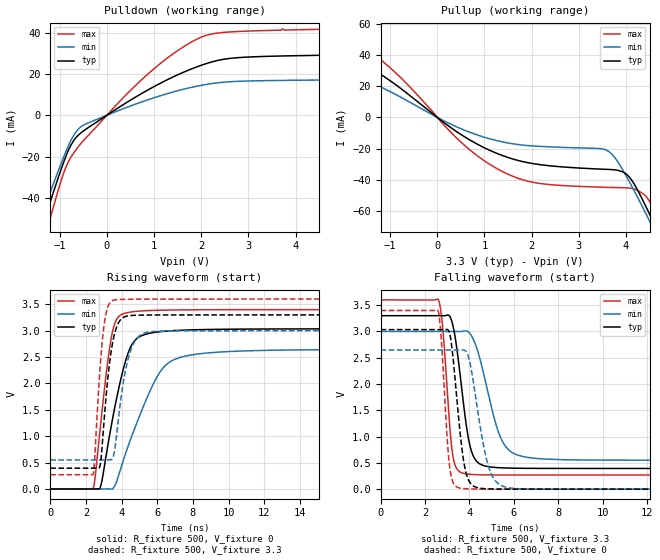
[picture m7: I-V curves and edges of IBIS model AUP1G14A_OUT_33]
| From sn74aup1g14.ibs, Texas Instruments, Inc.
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[Model]   AUP1G14A_OUT_33
Model_type  Output
Vref =   0
Rref =   1E6
Cref =   30p
Vmeas =   1.65
| variable   typ   min   max
C_comp   2.81pF   1.90pF   4.21pF
| C_pullup   3.21pF   1.90pF   4.21pF
| C_pulldown   2.42pF   2.21pF   2.99pF
[Temperature Range]   40   100   -40
| Ambient temperature   25   85   -40
[Voltage range]   3.3   3   3.6
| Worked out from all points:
|   slope of the pulldown table from 0 to 0.495 V, typ, clamps not added: 68.4 ohm
|   slope of the pullup table from 0 to 0.495 V, typ, clamps not added: 45.8 ohm
|   rising waveform, R_fixture 500, V_fixture 0: 20-80 % time 1.1ns typ, 1.89ns min, 693ps max; typ from 0 V to 3.04 V
|   falling waveform, R_fixture 500, V_fixture 3.3: 20-80 % time 532ps typ, 894ps min, 343ps max; typ from 3.3 V to 0.394 V
|   rising waveform, R_fixture 500, V_fixture 3.3: 20-80 % time 522ps typ, 676ps min, 407ps max; typ from 0.394 V to 3.3 V
|   falling waveform, R_fixture 500, V_fixture 0: 20-80 % time 434ps typ, 648ps min, 296ps max; typ from 3.04 V to 0 V
[Pulldown]
| AUP1G14A_OUT_33
|   Voltage   I(typ)   I(min)   I(max)
-3.6V     -218.7mA   -196.3mA   -248.6mA
-1.515V   -64.37mA   -57.31mA   -75.82mA
-1.39V    -55.35mA   -49.29mA   -65.41mA
-1.275V   -47.14mA   -42mA      -55.89mA
-870mV    -19.93mA   -17.62mA   -25.18mA
-720mV    -12.85mA   -10.38mA   -18.82mA
-545mV    -8.444mA   -5.509mA   -13.51mA
940mV     13.13mA    8.018mA    21.36mA
1.5V      19.56mA    11.86mA    31.27mA
2.045V    24.53mA    14.67mA    38.2mA
3.1V      28.27mA    16.63mA    40.81mA
7.2V      29.73mA    17.36mA    42.67mA
[Pullup]
| AUP1G14A_OUT_33
|   Voltage   I(typ)   I(min)   I(max)
-3.6V     42.88mA    27.27mA    57.92mA
-2.465V   31.53mA    19.52mA    45.85mA
-1.53V    32.87mA    22.09mA    44.95mA
-755mV    18.1mA     12.64mA    24.89mA
555mV     -11.98mA   -7.942mA   -17.3mA
1.65V     -27.07mA   -17.13mA   -38.31mA
3.61V     -33.32mA   -21.39mA   -44.82mA
4.08V     -38.63mA   -41.77mA   -45.28mA
4.375V    -54.25mA   -58.9mA    -49.24mA
4.565V    -66.24mA   -70.37mA   -57.33mA
4.775V    -80.02mA   -83.29mA   -71.37mA
7.2V      -250.7mA   -240.9mA   -257mA
[Ramp]
| AUP1G14A_OUT_33
| variable   typ   min   max
dV/dt_r   1.82/1.10E-09   1.59/1.89E-09   2.04/6.95E-10
dV/dt_f   1.75/5.38E-10   1.48/9.00E-10   2.01/3.46E-10
R_load = 500
[Rising Waveform]
| AUP1G14A_OUT_33
R_fixture =   500
C_fixture =   0
L_fixture =   0
V_fixture =   0
V_fixture_min = 0
V_fixture_max = 0
|   Time   V(typ)   V(min)   V(max)
0s        24.73nV    82.54nV    2.123nV
2.41ns    -1.838uV   -5.975uV   10.23mV
2.84ns    66.48mV    -28.42uV   1.273V
3.41ns    1.174V     -2.96mV    2.84V
3.69ns    1.666V     111.4mV    3.194V
4.155ns   2.345V     600.5mV    3.327V
4.785ns   2.829V     1.191V     3.366V
6.045ns   2.977V     2.158V     3.388V
7.545ns   3.012V     2.517V     3.395V
30.7ns    3.035V     2.647V     3.399V
[Falling Waveform]
| AUP1G14A_OUT_33
R_fixture =   500
C_fixture =   0
L_fixture =   0
V_fixture =   3.3
V_fixture_min = 3
V_fixture_max = 3.6
|   Time   V(typ)   V(min)   V(max)
0s        3.3V       3V         3.6V
2.605ns   3.3V       3V         3.6V
2.795ns   3.299V     3V         3.071V
3.235ns   3.143V     3V         683.3mV
3.735ns   1.614V     3.008V     299.9mV
4.01ns    847.1mV    2.966V     282.9mV
4.325ns   528.2mV    2.687V     275.4mV
5.39ns    406.8mV    991.7mV    270mV
6.41ns    397mV      620.5mV    269.4mV
30.7ns    394.1mV    550mV      269.3mV
[Rising Waveform]
| AUP1G14A_OUT_33
R_fixture =   500
C_fixture =   0
L_fixture =   0
V_fixture =   3.3
V_fixture_min = 3
V_fixture_max = 3.6
|   Time   V(typ)   V(min)   V(max)
0s        394.1mV    550mV      269.3mV
2.4ns     394.1mV    550mV      279.2mV
2.485ns   394.2mV    550mV      545.2mV
2.785ns   432.2mV    550mV      2.253V
2.975ns   1.103V     550.2mV    2.989V
3.26ns    2.198V     551.2mV    3.48V
3.545ns   2.854V     625.8mV    3.579V
4.37ns    3.282V     2.471V     3.596V
5.385ns   3.296V     2.966V     3.599V
30.7ns    3.3V       3V         3.6V
[Falling Waveform]
| AUP1G14A_OUT_33
R_fixture =   500
C_fixture =   0
L_fixture =   0
V_fixture =   0
V_fixture_min = 0
V_fixture_max = 0
|   Time   V(typ)   V(min)   V(max)
0s        3.035V     2.647V     3.399V
2.59ns    3.035V     2.647V     3.388V
2.725ns   3.035V     2.647V     2.88V
3.1ns     2.975V     2.647V     449mV
3.54ns    1.23V      2.647V     22.51mV
3.77ns    454mV      2.644V     9.155mV
4.03ns    120.3mV    2.385V     3.913mV
4.835ns   5.883mV    462.3mV    359.7uV
5.67ns    732.2uV    33.61mV    51.4uV
30.7ns    -41.62nV   32.74nV    -29.92nV
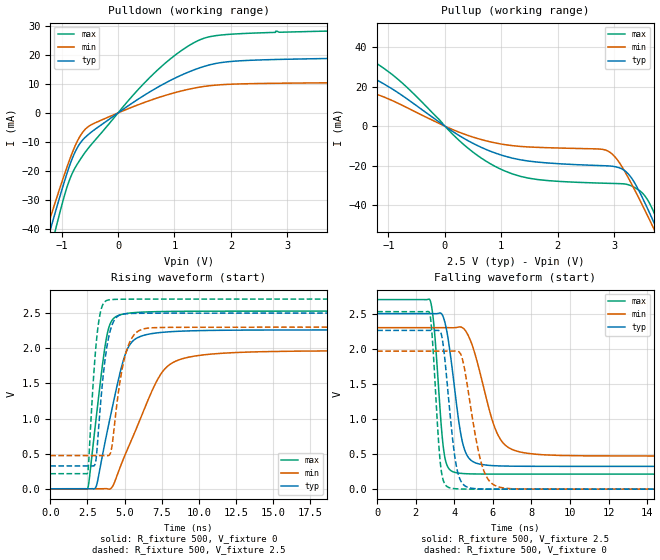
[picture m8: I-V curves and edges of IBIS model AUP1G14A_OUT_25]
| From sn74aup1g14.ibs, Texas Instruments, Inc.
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[Model]   AUP1G14A_OUT_25
Model_type  Output
Vref =   0
Rref =   1E6
Cref =   30p
Vmeas =   1.25
| variable   typ   min   max
C_comp   2.86pF   1.96pF   4.23pF
| C_pullup   3.21pF   1.96pF   4.23pF
| C_pulldown   2.51pF   2.22pF   3.08pF
[Temperature Range]   40   100   -40
| Ambient temperature   25   85   -40
[Voltage range]   2.5   2.3   2.7
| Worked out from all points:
|   slope of the pulldown table from 0 to 0.375 V, typ, clamps not added: 75.2 ohm
|   slope of the pullup table from 0 to 0.375 V, typ, clamps not added: 55.1 ohm
|   rising waveform, R_fixture 500, V_fixture 0: 20-80 % time 1.4ns typ, 2.4ns min, 861ps max; typ from 0 V to 2.26 V
|   falling waveform, R_fixture 500, V_fixture 2.5: 20-80 % time 634ps typ, 1.09ns min, 400ps max; typ from 2.5 V to 0.325 V
|   rising waveform, R_fixture 500, V_fixture 2.5: 20-80 % time 630ps typ, 806ps min, 486ps max; typ from 0.325 V to 2.5 V
|   falling waveform, R_fixture 500, V_fixture 0: 20-80 % time 507ps typ, 760ps min, 339ps max; typ from 2.26 V to 0 V
[Pulldown]
| AUP1G14A_OUT_25
|   Voltage   I(typ)   I(min)   I(max)
-3.6V     -214mA     -193.5mA   -239.7mA
-1.26V    -44.55mA   -39.92mA   -52.42mA
-1.205V   -40.74mA   -36.52mA   -48.02mA
-1.115V   -34.57mA   -31.02mA   -40.91mA
-800mV    -15.22mA   -13.22mA   -20.4mA
-685mV    -10.84mA   -8.445mA   -16.54mA
-540mV    -7.689mA   -4.911mA   -12.5mA
675mV     8.558mA    5.038mA    14.35mA
1.105V    12.9mA     7.5mA      21.28mA
1.52V     16.03mA    9.129mA    25.76mA
2.585V    18.34mA    10.19mA    27.69mA
7.2V      19.61mA    10.73mA    29.61mA
[Pullup]
| AUP1G14A_OUT_25
|   Voltage   I(typ)   I(min)   I(max)
-3.6V     37.28mA    23.5mA     50.35mA
-2.355V   24.65mA    15.21mA    35.57mA
-1.425V   26.01mA    17.2mA     35.58mA
-760mV    15.58mA    10.63mA    21.96mA
405mV     -7.279mA   -4.651mA   -11.04mA
1.05V     -15.07mA   -9.293mA   -22.54mA
2.845V    -20.04mA   -12.07mA   -28.88mA
3.17V     -22.17mA   -22.09mA   -29.2mA
3.455V    -33.67mA   -37.48mA   -32.73mA
3.685V    -47.61mA   -50.92mA   -42.5mA
3.82V     -56.28mA   -59.04mA   -51.47mA
7.2V      -294.7mA   -278.7mA   -311.5mA
[Ramp]
| AUP1G14A_OUT_25
| variable   typ   min   max
dV/dt_r   1.36/1.40E-09   1.18/2.41E-09   1.52/8.62E-10
dV/dt_f   1.31/6.40E-10   1.10/1.10E-09   1.50/4.05E-10
R_load = 500
[Rising Waveform]
| AUP1G14A_OUT_25
R_fixture =   500
C_fixture =   0
L_fixture =   0
V_fixture =   0
V_fixture_min = 0
V_fixture_max = 0
|   Time   V(typ)   V(min)   V(max)
0s        19.04nV    76.96nV    1.464nV
2.52ns    -19.26uV   -183.7nV   4.866mV
3.1ns     39.45mV    -26.1uV    1.03V
3.77ns    751.8mV    1.393mV    2.135V
4.62ns    1.584V     261.2mV    2.47V
5.135ns   1.961V     533.1mV    2.495V
5.69ns    2.126V     806.6mV    2.508V
7.415ns   2.224V     1.625V     2.522V
8.915ns   2.244V     1.853V     2.526V
32.79ns   2.261V     1.966V     2.528V
[Falling Waveform]
| AUP1G14A_OUT_25
R_fixture =   500
C_fixture =   0
L_fixture =   0
V_fixture =   2.5
V_fixture_min = 2.3
V_fixture_max = 2.7
|   Time   V(typ)   V(min)   V(max)
0s        2.5V       2.3V       2.7V
2.74ns    2.5V       2.3V       2.693V
2.955ns   2.499V     2.3V       2.3V
3.46ns    2.426V     2.3V       535.6mV
4.025ns   1.412V     2.3V       239.4mV
4.39ns    710.1mV    2.304V     224mV
4.77ns    437mV      2.161V     218.4mV
6.19ns    332.6mV    814.1mV    214.6mV
7.385ns   326.4mV    531.3mV    214.4mV
32.79ns   324.7mV    472mV      214.4mV
[Rising Waveform]
| AUP1G14A_OUT_25
R_fixture =   500
C_fixture =   0
L_fixture =   0
V_fixture =   2.5
V_fixture_min = 2.3
V_fixture_max = 2.7
|   Time   V(typ)   V(min)   V(max)
0s        324.7mV    472mV      214.4mV
2.515ns   324.7mV    472mV      226.8mV
2.98ns    335.3mV    472mV      1.789V
3.155ns   586.1mV    472mV      2.205V
3.44ns    1.348V     472.2mV    2.566V
3.805ns   2.014V     472.1mV    2.68V
4.125ns   2.312V     573.9mV    2.693V
5.08ns    2.491V     1.928V     2.698V
6.215ns   2.498V     2.272V     2.699V
32.79ns   2.5V       2.3V       2.7V
[Falling Waveform]
| AUP1G14A_OUT_25
R_fixture =   500
C_fixture =   0
L_fixture =   0
V_fixture =   0
V_fixture_min = 0
V_fixture_max = 0
|   Time   V(typ)   V(min)   V(max)
0s        2.261V     1.966V     2.528V
2.71ns    2.261V     1.966V     2.514V
2.86ns    2.26V      1.966V     2.15V
3.295ns   2.231V     1.966V     325mV
3.785ns   1.054V     1.966V     17.17mV
4.075ns   377mV      1.968V     6.117mV
4.385ns   94.51mV    1.886V     2.296mV
5.42ns    3.052mV    352.9mV    129.4uV
6.37ns    366.4uV    25.92mV    18.05uV
32.79ns   -40.91nV   13.26nV    -41.92nV
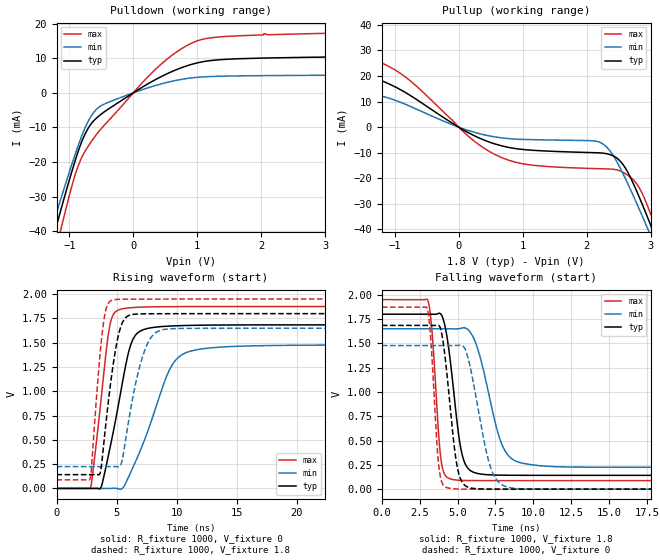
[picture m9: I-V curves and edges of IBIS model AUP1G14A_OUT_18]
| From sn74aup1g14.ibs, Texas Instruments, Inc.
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[Model]   AUP1G14A_OUT_18
Model_type  Output
Vref =   0
Rref =   1E6
Cref =   30p
Vmeas =   0.9
| variable   typ   min   max
C_comp   2.88pF   2.03pF   4.17pF
| C_pullup   3.17pF   2.03pF   4.17pF
| C_pulldown   2.60pF   2.23pF   3.12pF
[Temperature Range]   40   100   -40
| Ambient temperature   25   85   -40
[Voltage range]   1.8   1.65   1.95
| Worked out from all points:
|   slope of the pulldown table from 0 to 0.27 V, typ, clamps not added: 88.6 ohm
|   slope of the pullup table from 0 to 0.27 V, typ, clamps not added: 73.6 ohm
|   rising waveform, R_fixture 1000, V_fixture 0: 20-80 % time 1.58ns typ, 2.62ns min, 994ps max; typ from 0 V to 1.68 V
|   falling waveform, R_fixture 1000, V_fixture 1.8: 20-80 % time 758ps typ, 1.33ns min, 466ps max; typ from 1.8 V to 0.142 V
|   rising waveform, R_fixture 1000, V_fixture 1.8: 20-80 % time 1.03ns typ, 1.42ns min, 733ps max; typ from 0.142 V to 1.8 V
|   falling waveform, R_fixture 1000, V_fixture 0: 20-80 % time 682ps typ, 1.11ns min, 431ps max; typ from 1.68 V to 0 V
[Pulldown]
| AUP1G14A_OUT_18
|   Voltage   I(typ)   I(min)   I(max)
-3.6V     -208.6mA   -189.9mA   -231.7mA
-1.27V    -43.16mA   -39.01mA   -50.14mA
-1.215V   -39.42mA   -35.66mA   -45.88mA
-1.125V   -33.38mA   -30.25mA   -38.97mA
-850mV    -16.31mA   -14.68mA   -20.63mA
-710mV    -10.41mA   -8.408mA   -15.6mA
-555mV    -6.973mA   -4.411mA   -11.55mA
360mV     3.96mA     2.185mA    7.039mA
705mV     6.927mA    3.722mA    12.18mA
1.03V     8.784mA    4.527mA    15.22mA
2.04V     10.05mA    4.966mA    17.1mA
7.2V      11.18mA    5.355mA    18.77mA
[Pullup]
| AUP1G14A_OUT_18
|   Voltage   I(typ)   I(min)   I(max)
-3.6V     32.09mA    19.71mA    43.84mA
-3.16V    27.19mA    16.62mA    37.96mA
-2.12V    17.93mA    10.78mA    26.5mA
-1.525V   19.29mA    11.78mA    27.75mA
-1.155V   17.65mA    11.82mA    24.55mA
680mV     -7.373mA   -4.228mA   -12mA
2.185V    -10.05mA   -5.721mA   -16.26mA
2.485V    -12.35mA   -14.1mA    -16.81mA
2.725V    -21.81mA   -26.61mA   -20.47mA
2.94V     -34.55mA   -38.91mA   -30.08mA
3.085V    -43.74mA   -47.5mA    -39.77mA
7.2V      -334.8mA   -315.6mA   -357.6mA
[Ramp]
| AUP1G14A_OUT_18
| variable   typ   min   max
dV/dt_r   1.01/1.59E-09   0.89/2.63E-09   1.13/9.96E-10
dV/dt_f   1.00/7.63E-10   0.86/1.34E-09   1.12/4.70E-10
R_load = 1000
[Rising Waveform]
| AUP1G14A_OUT_18
R_fixture =   1000
C_fixture =   0
L_fixture =   0
V_fixture =   0
V_fixture_min = 0
V_fixture_max = 0
|   Time   V(typ)   V(min)   V(max)
0s        17.12nV    87.22nV    1.127nV
2.84ns    -18.28uV   -646.2nV   11.47mV
3.695ns   9.341mV    -15.97uV   897.8mV
4.35ns    356.4mV    100.2uV    1.615V
5.15ns    856.8mV    -3.738mV   1.837V
5.99ns    1.396V     114.6mV    1.859V
6.615ns   1.584V     286.2mV    1.864V
9.355ns   1.671V     1.207V     1.872V
10.85ns   1.678V     1.401V     1.873V
35.9ns    1.685V     1.477V     1.873V
[Falling Waveform]
| AUP1G14A_OUT_18
R_fixture =   1000
C_fixture =   0
L_fixture =   0
V_fixture =   1.8
V_fixture_min = 1.65
V_fixture_max = 1.95
|   Time   V(typ)   V(min)   V(max)
0s        1.8V       1.65V      1.95V
3.04ns    1.8V       1.65V      1.94V
3.305ns   1.8V       1.65V      1.635V
3.885ns   1.802V     1.65V      327.7mV
4.495ns   1.349V     1.65V      106.9mV
5.12ns    504.2mV    1.651V     91.79mV
5.58ns    237.1mV    1.653V     89.29mV
7.885ns   144.1mV    475.2mV    87.92mV
9.07ns    142.7mV    275.5mV    87.9mV
35.9ns    142.2mV    224.7mV    87.89mV
[Rising Waveform]
| AUP1G14A_OUT_18
R_fixture =   1000
C_fixture =   0
L_fixture =   0
V_fixture =   1.8
V_fixture_min = 1.65
V_fixture_max = 1.95
|   Time   V(typ)   V(min)   V(max)
0s        142.2mV    224.7mV    87.89mV
2.81ns    142.2mV    224.7mV    105.7mV
3.575ns   144.3mV    224.7mV    1.313V
3.825ns   329.3mV    224.7mV    1.621V
4.58ns    1.155V     225.1mV    1.936V
5.33ns    1.656V     237.6mV    1.948V
5.675ns   1.747V     438.1mV    1.948V
7.095ns   1.797V     1.328V     1.95V
8.595ns   1.799V     1.625V     1.95V
35.9ns    1.8V       1.65V      1.95V
[Falling Waveform]
| AUP1G14A_OUT_18
R_fixture =   1000
C_fixture =   0
L_fixture =   0
V_fixture =   0
V_fixture_min = 0
V_fixture_max = 0
|   Time   V(typ)   V(min)   V(max)
0s        1.685V     1.478V     1.873V
3.01ns    1.685V     1.478V     1.853V
3.225ns   1.684V     1.478V     1.549V
3.755ns   1.685V     1.477V     242.9mV
4.295ns   1.186V     1.477V     15.78mV
4.85ns    351.8mV    1.478V     2.878mV
5.265ns   81.8mV     1.478V     842.6uV
7.14ns    587.3uV    241.9mV    10.75uV
8.265ns   85uV       22.2mV     1.813uV
35.9ns    -64.9nV    26.46nV    -58.17nV
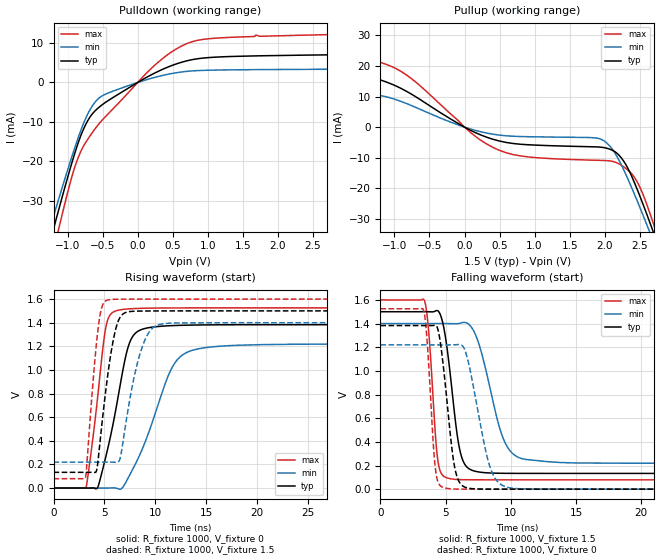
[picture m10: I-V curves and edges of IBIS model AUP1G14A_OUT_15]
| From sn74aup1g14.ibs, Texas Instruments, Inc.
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[Model]   AUP1G14A_OUT_15
Model_type  Output
Vref =   0
Rref =   1E6
Cref =   30p
Vmeas =   0.75
| variable   typ   min   max
C_comp   2.88pF   2.08pF   4.08pF
| C_pullup   3.12pF   2.08pF   4.08pF
| C_pulldown   2.65pF   2.24pF   3.14pF
[Temperature Range]   40   100   -40
| Ambient temperature   25   85   -40
[Voltage range]   1.5   1.4   1.6
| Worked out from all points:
|   slope of the pulldown table from 0 to 0.225 V, typ, clamps not added: 101 ohm
|   slope of the pullup table from 0 to 0.225 V, typ, clamps not added: 90.4 ohm
|   rising waveform, R_fixture 1000, V_fixture 0: 20-80 % time 1.9ns typ, 3.13ns min, 1.2ns max; typ from 0 V to 1.38 V
|   falling waveform, R_fixture 1000, V_fixture 1.5: 20-80 % time 895ps typ, 1.6ns min, 543ps max; typ from 1.5 V to 0.133 V
|   rising waveform, R_fixture 1000, V_fixture 1.5: 20-80 % time 1.23ns typ, 1.66ns min, 881ps max; typ from 0.133 V to 1.5 V
|   falling waveform, R_fixture 1000, V_fixture 0: 20-80 % time 806ps typ, 1.32ns min, 503ps max; typ from 1.38 V to 0 V
[Pulldown]
| AUP1G14A_OUT_15
|   Voltage   I(typ)   I(min)   I(max)
-3.6V     -206.1mA   -188.4mA   -227.8mA
-1.265V   -41.59mA   -37.94mA   -47.65mA
-1.21V    -37.9mA    -34.62mA   -43.48mA
-1.11V    -31.29mA   -28.67mA   -36mA
-945mV    -20.84mA   -19.21mA   -24.37mA
-855mV    -15.7mA    -14.39mA   -19.43mA
-720mV    -9.972mA   -8.297mA   -14.65mA
-570mV    -6.595mA   -4.269mA   -10.91mA
260mV     2.544mA    1.373mA    4.642mA
810mV     5.906mA    2.979mA    10.53mA
1.685V    6.762mA    3.268mA    12.01mA
7.2V      7.827mA    3.609mA    13.77mA
[Pullup]
| AUP1G14A_OUT_15
|   Voltage   I(typ)   I(min)   I(max)
-3.6V     29.66mA    17.95mA    40.7mA
-2.925V   22.54mA    13.64mA    31.9mA
-2.13V    15.77mA    9.503mA    23.16mA
-1.025V   13.91mA    9.322mA    19.64mA
130mV     -1.525mA   -910.1uA   -2.565mA
590mV     -4.979mA   -2.819mA   -8.32mA
1.925V    -6.506mA   -3.765mA   -10.85mA
2.175V    -8.513mA   -9.57mA    -11.67mA
2.395V    -16.55mA   -20.31mA   -15.49mA
2.615V    -29.32mA   -32.63mA   -26.15mA
2.72V     -35.89mA   -38.74mA   -33.2mA
7.2V      -352.6mA   -330.3mA   -379.5mA
[Ramp]
| AUP1G14A_OUT_15
| variable   typ   min   max
dV/dt_r   0.83/1.91E-09   0.74/3.16E-09   0.92/1.21E-09
dV/dt_f   0.83/9.02E-10   0.71/1.62E-09   0.92/5.50E-10
R_load = 1000
[Rising Waveform]
| AUP1G14A_OUT_15
R_fixture =   1000
C_fixture =   0
L_fixture =   0
V_fixture =   0
V_fixture_min = 0
V_fixture_max = 0
|   Time   V(typ)   V(min)   V(max)
0s        16.57nV    92.2nV     986.7pV
3.2ns     -16.51uV   -818.6nV   8.114mV
4.3ns     165.2uV    -15.04uV   741.5mV
5.045ns   233mV      -450.7nV   1.313V
5.92ns    573mV      1.31mV     1.493V
7.115ns   1.123V     50.96mV    1.515V
7.865ns   1.294V     173.4mV    1.519V
11.44ns   1.374V     984.6mV    1.525V
13.08ns   1.379V     1.148V     1.525V
34.99ns   1.383V     1.22V      1.525V
[Falling Waveform]
| AUP1G14A_OUT_15
R_fixture =   1000
C_fixture =   0
L_fixture =   0
V_fixture =   1.5
V_fixture_min = 1.4
V_fixture_max = 1.6
|   Time   V(typ)   V(min)   V(max)
0s        1.5V       1.4V       1.6V
3.375ns   1.5V       1.4V       1.594V
3.71ns    1.5V       1.4V       1.321V
4.375ns   1.509V     1.4V       268.8mV
5.04ns    1.247V     1.4V       98.21mV
6.07ns    341.3mV    1.402V     80.91mV
7.095ns   156.9mV    1.349V     79.34mV
9.335ns   134.3mV    452.1mV    79.09mV
10.7ns    133.4mV    263.3mV    79.08mV
34.99ns   133.1mV    219.3mV    79.08mV
[Rising Waveform]
| AUP1G14A_OUT_15
R_fixture =   1000
C_fixture =   0
L_fixture =   0
V_fixture =   1.5
V_fixture_min = 1.4
V_fixture_max = 1.6
|   Time   V(typ)   V(min)   V(max)
0s        133.1mV    219.3mV    79.08mV
3.15ns    133.1mV    219.3mV    91.06mV
4.25ns    155.7mV    219.3mV    1.25V
4.675ns   477.6mV    219.4mV    1.508V
5.185ns   861.7mV    219.5mV    1.587V
5.92ns    1.273V     218.9mV    1.598V
6.575ns   1.45V      262.9mV    1.599V
8.34ns    1.498V     1.089V     1.6V
10.12ns   1.499V     1.376V     1.6V
34.99ns   1.5V       1.4V       1.6V
[Falling Waveform]
| AUP1G14A_OUT_15
R_fixture =   1000
C_fixture =   0
L_fixture =   0
V_fixture =   0
V_fixture_min = 0
V_fixture_max = 0
|   Time   V(typ)   V(min)   V(max)
0s        1.383V     1.22V      1.525V
3.31ns    1.383V     1.22V      1.513V
4.195ns   1.385V     1.22V      194.4mV
4.795ns   1.069V     1.219V     15mV
5.54ns    292.5mV    1.22V      1.947mV
6ns       70.66mV    1.222V     546.2uV
6.68ns    9.997mV    1.102V     95.86uV
8.39ns    288.8uV    192.1mV    3.312uV
9.565ns   48.93uV    21.44mV    491nV
34.99ns   -65.44nV   -15.26nV   -72.82nV
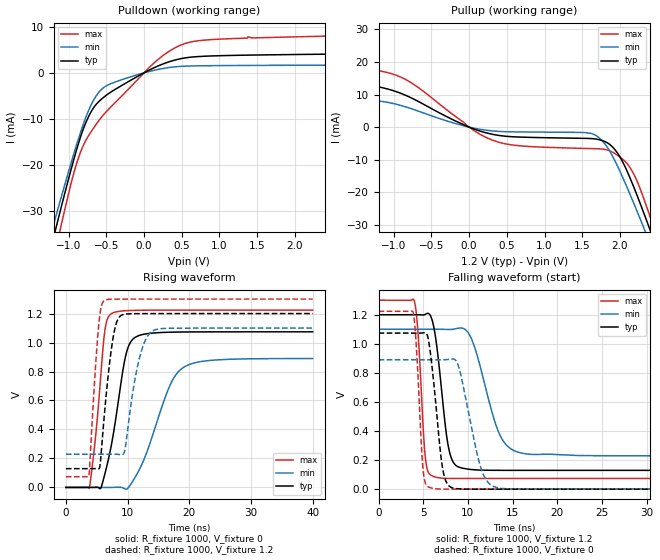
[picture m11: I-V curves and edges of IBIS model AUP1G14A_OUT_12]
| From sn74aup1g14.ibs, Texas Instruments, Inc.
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[Model]   AUP1G14A_OUT_12
Model_type  Output
Vref =   0
Rref =   1E6
Cref =   30p
Vmeas =   0.6
| variable   typ   min   max
C_comp   2.85pF   2.12pF   3.93pF
| C_pullup   3.03pF   2.12pF   3.93pF
| C_pulldown   2.67pF   2.23pF   3.17pF
[Temperature Range]   40   100   -40
| Ambient temperature   25   85   -40
[Voltage range]   1.2   1.1   1.3
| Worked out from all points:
|   slope of the pulldown table from 0 to 0.18 V, typ, clamps not added: 125 ohm
|   slope of the pullup table from 0 to 0.18 V, typ, clamps not added: 123 ohm
|   rising waveform, R_fixture 1000, V_fixture 0: 20-80 % time 2.45ns typ, 4.44ns min, 1.51ns max; typ from 0 V to 1.07 V
|   falling waveform, R_fixture 1000, V_fixture 1.2: 20-80 % time 1.16ns typ, 2.36ns min, 662ps max; typ from 1.2 V to 0.129 V
|   rising waveform, R_fixture 1000, V_fixture 1.2: 20-80 % time 1.56ns typ, 2.11ns min, 1.1ns max; typ from 0.129 V to 1.2 V
|   falling waveform, R_fixture 1000, V_fixture 0: 20-80 % time 1.05ns typ, 1.83ns min, 618ps max; typ from 1.07 V to 0 V
[Pulldown]
| AUP1G14A_OUT_12
|   Voltage   I(typ)   I(min)   I(max)
-3.6V     -203.6mA   -186.6mA   -224.6mA
-1.215V   -36.77mA   -33.88mA   -41.55mA
-1.165V   -33.49mA   -30.92mA   -37.89mA
-1.12V    -30.57mA   -28.28mA   -34.63mA
-1.08V    -28mA      -25.95mA   -31.76mA
-930mV    -18.76mA   -17.53mA   -21.68mA
-820mV    -12.87mA   -11.86mA   -16.33mA
-695mV    -8.261mA   -6.747mA   -12.62mA
-580mV    -5.938mA   -3.862mA   -9.962mA
160mV     1.298mA    643.5uA    2.533mA
610mV     3.376mA    1.481mA    6.659mA
7.2V      4.761mA    1.852mA    9.574mA
[Pullup]
| AUP1G14A_OUT_12
|   Voltage   I(typ)   I(min)   I(max)
-3.6V     26.64mA    8.226mA    37.8mA
-3.065V   21.41mA    10.49mA    30.92mA
-2.05V    13.06mA    7.529mA    19.66mA
-955mV    10.79mA    6.951mA    15.81mA
400mV     -2.561mA   -1.314mA   -4.679mA
1.61V     -3.491mA   -1.891mA   -6.566mA
1.87V     -5.387mA   -7.563mA   -7.321mA
2.095V    -13.49mA   -18.49mA   -11.17mA
2.33V     -27.16mA   -31.66mA   -22.8mA
2.44V     -34.07mA   -38.08mA   -30.25mA
2.51V     -38.55mA   -42.22mA   -35.17mA
7.2V      -371mA     -348.5mA   -398.6mA
[Ramp]
| AUP1G14A_OUT_12
| variable   typ   min   max
dV/dt_r   0.65/2.48E-09   0.54/4.51E-09   0.74/1.52E-09
dV/dt_f   0.65/1.17E-09   0.53/2.38E-09   0.74/6.71E-10
R_load = 1000
[Rising Waveform]
| AUP1G14A_OUT_12
R_fixture =   1000
C_fixture =   0
L_fixture =   0
V_fixture =   0
V_fixture_min = 0
V_fixture_max = 0
|   Time   V(typ)   V(min)   V(max)
0s        17.04nV    106.6nV    899pV
3.825ns   -9.138uV   -63.22nV   1.752mV
4.915ns   799.8uV    165.3nV    393.5mV
6.255ns   82.79mV    -9.699uV   1.061V
7.305ns   277.2mV    -21.95uV   1.197V
9.66ns    902.6mV    -11.43mV   1.219V
11.34ns   1.039V     78.03mV    1.222V
16.78ns   1.071V     695.7mV    1.224V
19.02ns   1.073V     827mV      1.224V
40ns      1.074V     889.7mV    1.224V
[Falling Waveform]
| AUP1G14A_OUT_12
R_fixture =   1000
C_fixture =   0
L_fixture =   0
V_fixture =   1.2
V_fixture_min = 1.1
V_fixture_max = 1.3
|   Time   V(typ)   V(min)   V(max)
0s        1.2V       1.1V       1.3V
4ns       1.2V       1.1V       1.294V
4.425ns   1.2V       1.1V       1.064V
5.215ns   1.202V     1.1V       229.6mV
5.935ns   1.174V     1.1V       93.42mV
7.765ns   307.7mV    1.099V     74.14mV
8.865ns   154.8mV    1.107V     73.63mV
10.34ns   135.3mV    1.041V     73.55mV
15.2ns    129.5mV    264.2mV    73.54mV
40ns      129.5mV    229.3mV    73.54mV
[Rising Waveform]
| AUP1G14A_OUT_12
R_fixture =   1000
C_fixture =   0
L_fixture =   0
V_fixture =   1.2
V_fixture_min = 1.1
V_fixture_max = 1.3
|   Time   V(typ)   V(min)   V(max)
0s        129.5mV    229.3mV    73.54mV
3.74ns    129.5mV    229.3mV    84.1mV
5.25ns    128.3mV    229.3mV    1.086V
6.22ns    492.8mV    229.3mV    1.29V
7.365ns   951.4mV    229.5mV    1.299V
8.38ns    1.157V     228.4mV    1.3V
9.495ns   1.195V     246.9mV    1.3V
11.73ns   1.199V     858.5mV    1.3V
14.05ns   1.2V       1.08V      1.3V
40ns      1.2V       1.1V       1.3V
[Falling Waveform]
| AUP1G14A_OUT_12
R_fixture =   1000
C_fixture =   0
L_fixture =   0
V_fixture =   0
V_fixture_min = 0
V_fixture_max = 0
|   Time   V(typ)   V(min)   V(max)
0s        1.074V     889.8mV    1.224V
3.86ns    1.074V     889.8mV    1.217V
4.955ns   1.075V     889.8mV    151.4mV
5.59ns    1.024V     889.7mV    15.06mV
7.115ns   162.8mV    889.7mV    476uV
8.115ns   12.68mV    894.8mV    45.19uV
9.03ns    2.007mV    828.5mV    6.879uV
11.49ns   49.37uV    138.4mV    480.8nV
12.86ns   9.536uV    18.81mV    178.1nV
40ns      -97.76nV   294.9nV    -57.13nV
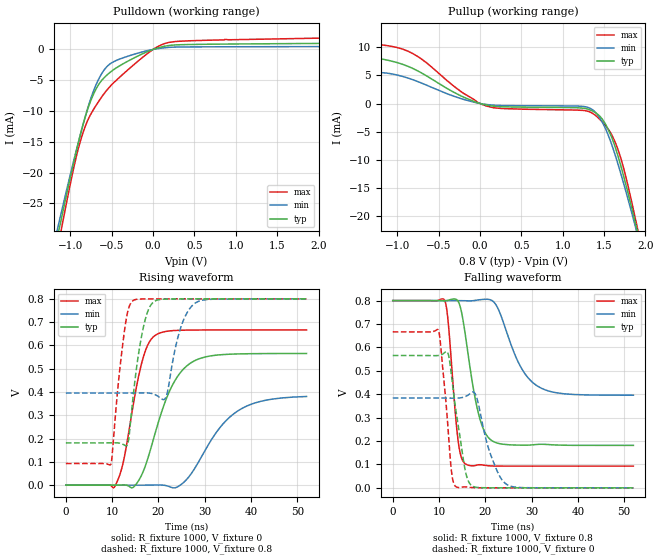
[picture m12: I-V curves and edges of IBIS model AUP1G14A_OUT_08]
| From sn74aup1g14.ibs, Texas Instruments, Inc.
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[Model]   AUP1G14A_OUT_08
Model_type  Output
Vref =   0
Rref =   1E6
Cref =   30p
Vmeas =   0.4
| variable   typ   min   max
C_comp   2.71pF   2.19pF   3.34pF
| C_pullup   2.77pF   2.20pF   3.34pF
| C_pulldown   2.64pF   2.19pF   3.08pF
[Temperature Range]   40   100   -40
| Ambient temperature   25   85   -40
[Voltage range]   0.8   0.8   0.8
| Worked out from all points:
|   slope of the pulldown table from 0 to 0.12 V, typ, clamps not added: 257 ohm
|   slope of the pullup table from 0 to 0.12 V, typ, clamps not added: 309 ohm
|   rising waveform, R_fixture 1000, V_fixture 0: 20-80 % time 5.99ns typ, 8.2ns min, 3.75ns max; typ from 0 V to 0.565 V
|   falling waveform, R_fixture 1000, V_fixture 0.8: 20-80 % time 3.17ns typ, 5.29ns min, 1.73ns max; typ from 0.8 V to 0.181 V
|   rising waveform, R_fixture 1000, V_fixture 0.8: 20-80 % time 2.6ns typ, 3.04ns min, 2.2ns max; typ from 0.181 V to 0.8 V
|   falling waveform, R_fixture 1000, V_fixture 0: 20-80 % time 2.47ns typ, 3.41ns min, 1.69ns max; typ from 0.566 V to 0 V
[Pulldown]
| AUP1G14A_OUT_08
|   Voltage   I(typ)   I(min)   I(max)
-3.6V     -200.3mA   -184.7mA   -219.1mA
-1.155V   -30.43mA   -29.11mA   -32.45mA
-1.105V   -27.26mA   -26.22mA   -28.93mA
-940mV    -17.24mA   -17.01mA   -18.09mA
-865mV    -13.13mA   -13.1mA    -14.27mA
-745mV    -8.043mA   -7.657mA   -10.32mA
-630mV    -5.174mA   -4.128mA   -7.88mA
-470mV    -3.218mA   -1.946mA   -5.328mA
5mV       23.8uA     12.51uA    45.54uA
245mV     711.3uA    371.9uA    1.246mA
870mV     872.1uA    431.7uA    1.618mA
7.2V      1.459mA    578.6uA    3.138mA
[Pullup]
| AUP1G14A_OUT_08
|   Voltage   I(typ)   I(min)   I(max)
-3.6V     2.784mA    339.2uA    9.474mA
-2.56V    3.921mA    663.8uA    11.14mA
-2.01V    6.261mA    1.269mA    13.37mA
-1.185V   7.906mA    5.477mA    10.41mA
-800mV    6.149mA    4.169mA    8.776mA
80mV      -287uA     -177.3uA   -461.9uA
1.285V    -921uA     -607uA     -1.305mA
1.455V    -2.355mA   -2.736mA   -2.902mA
1.625V    -7.333mA   -8.725mA   -6.56mA
1.74V     -13.09mA   -14.38mA   -11.68mA
1.905V    -22.78mA   -23.32mA   -22.23mA
7.2V      -396.8mA   -367.4mA   -431.7mA
[Ramp]
| AUP1G14A_OUT_08
| variable   typ   min   max
dV/dt_r   0.35/6.07E-09   0.24/8.33E-09   0.41/3.80E-09
dV/dt_f   0.38/3.19E-09   0.25/5.32E-09   0.43/1.75E-09
R_load = 1000
[Rising Waveform]
| AUP1G14A_OUT_08
R_fixture =   1000
C_fixture =   0
L_fixture =   0
V_fixture =   0
V_fixture_min = 0
V_fixture_max = 0
|   Time   V(typ)   V(min)   V(max)
0s        23.71nV    153.5nV    1.008nV
10.58ns   -1.636uV   -179.1nV   -5.57mV
12.46ns   579.6uV    -2.161uV   104mV
15.16ns   3.603mV    -11.93uV   411.8mV
17.21ns   84.33mV    41.3uV     578.2mV
19.41ns   230.9mV    524.6uV    644.6mV
23.25ns   437.9mV    -11.54mV   663.8mV
27.73ns   533.5mV    68.38mV    666.2mV
37.17ns   563.5mV    319mV      666.5mV
52ns      565.5mV    380.8mV    666.5mV
[Falling Waveform]
| AUP1G14A_OUT_08
R_fixture =   1000
C_fixture =   0
L_fixture =   0
V_fixture =   0.8
V_fixture_min = 0.8
V_fixture_max = 0.8
|   Time   V(typ)   V(min)   V(max)
0s        800mV      800mV      800mV
11.26ns   799mV      800mV      799.2mV
12ns      801.7mV    800mV      704.4mV
14.11ns   797.4mV    799.9mV    203.4mV
15.71ns   649.7mV    799.4mV    102.1mV
18.53ns   316.9mV    803mV      98.53mV
21.4ns    201.9mV    800.8mV    93.5mV
27.47ns   182.6mV    523.5mV    92.73mV
31.1ns    185.3mV    437mV      92.72mV
52ns      181.5mV    395.7mV    92.72mV
[Rising Waveform]
| AUP1G14A_OUT_08
R_fixture =   1000
C_fixture =   0
L_fixture =   0
V_fixture =   0.8
V_fixture_min = 0.8
V_fixture_max = 0.8
|   Time   V(typ)   V(min)   V(max)
0s        181.5mV    395.5mV    92.72mV
9.73ns    181.6mV    395.5mV    90.69mV
13.29ns   173.6mV    395.6mV    738.4mV
14.52ns   377.9mV    395.7mV    792.5mV
16.84ns   685.8mV    396.4mV    799.7mV
19.24ns   790.5mV    389mV      799.9mV
21.6ns    799.1mV    377mV      800mV
24.72ns   799.8mV    670.4mV    800mV
28.04ns   800mV      783mV      800mV
52ns      800mV      800mV      800mV
[Falling Waveform]
| AUP1G14A_OUT_08
R_fixture =   1000
C_fixture =   0
L_fixture =   0
V_fixture =   0
V_fixture_min = 0
V_fixture_max = 0
|   Time   V(typ)   V(min)   V(max)
0s        565.5mV    384mV      666.5mV
9.885ns   565.5mV    383.8mV    672.7mV
11.97ns   573.2mV    383.4mV    248.6mV
12.79ns   463.2mV    383.2mV    55.27mV
13.7ns    323.9mV    383.2mV    4.279mV
15.79ns   63.41mV    391mV      3.954mV
17.4ns    5.954mV    409.4mV    947.6uV
21.18ns   172uV      140.4mV    9.132uV
24.7ns    12.96uV    13.7mV     543.9nV
52ns      -19.68nV   545.4nV    -93.34nV
